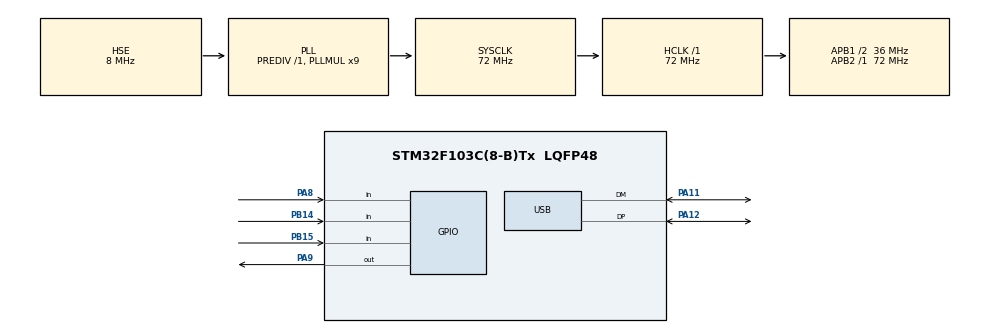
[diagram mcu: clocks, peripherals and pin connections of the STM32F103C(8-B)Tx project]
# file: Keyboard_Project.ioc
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Mcu.Family=STM32F1
Mcu.Name=STM32F103C(8-B)Tx
Mcu.Package=LQFP48
NVIC.PriorityGroup=NVIC_PRIORITYGROUP_4
NVIC.USB_LP_CAN1_RX0_IRQn=true\:0\:0\:false\:false\:true\:false\:true
PA11.Mode=Device
PA11.Signal=USB_DM
PA12.Mode=Device
PA12.Signal=USB_DP
PA13.Mode=Serial_Wire
PA13.Signal=SYS_JTMS-SWDIO
PA14.Mode=Serial_Wire
PA14.Signal=SYS_JTCK-SWCLK
PA8.Signal=GPIO_Input
PA9.Signal=GPIO_Output
PB14.Signal=GPIO_Input
PB15.Signal=GPIO_Input
PD0-OSC_IN.Mode=HSE-External-Oscillator
PD0-OSC_IN.Signal=RCC_OSC_IN
PD1-OSC_OUT.Mode=HSE-External-Oscillator
PD1-OSC_OUT.Signal=RCC_OSC_OUT
ProjectManager.HeapSize=0x200
ProjectManager.StackSize=0x400
ProjectManager.TargetToolchain=STM32CubeIDE
RCC.AHBFreq_Value=72000000
RCC.APB1CLKDivider=RCC_HCLK_DIV2
RCC.APB1Freq_Value=36000000
RCC.APB1TimFreq_Value=72000000
RCC.APB2Freq_Value=72000000
RCC.APB2TimFreq_Value=72000000
RCC.HCLKFreq_Value=72000000
RCC.PLLMUL=RCC_PLL_MUL9
RCC.SYSCLKFreq_VALUE=72000000
RCC.SYSCLKSource=RCC_SYSCLKSOURCE_PLLCLK
RCC.USBFreq_Value=48000000
RCC.USBPrescaler=RCC_USBCLKSOURCE_PLL_DIV1_5
USB_DEVICE.CLASS_NAME_FS=HID
USB_DEVICE.PRODUCT_STRING_HID_FS=Keyboard Project STM32
USB_DEVICE.VirtualMode=Hid
USB_DEVICE.VirtualModeFS=Hid_FS
VP_USB_DEVICE_VS_USB_DEVICE_HID_FS.Mode=HID_FS
board=custom

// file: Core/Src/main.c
/* USER CODE BEGIN Header */
/**
  ******************************************************************************
  * @file           : main.c
  * @brief          : Main program body
  ******************************************************************************
  * @attention
  *
  * <h2><center>&copy; Copyright (c) 2022 STMicroelectronics.
  * All rights reserved.</center></h2>
  *
  * This software component is licensed by ST under BSD 3-Clause license,
  * the "License"; You may not use this file except in compliance with the
  * License. You may obtain a copy of the License at:
  *                        opensource.org/licenses/BSD-3-Clause
  *
  ******************************************************************************
  */
/* USER CODE END Header */
#include "main.h"
#include "usb_device.h"

/* USER CODE BEGIN Includes */
#include "usbd_hid.h"
/* USER CODE END Includes */

void SystemClock_Config(void);
static void MX_GPIO_Init(void);

/* USER CODE BEGIN 0 */
extern USBD_HandleTypeDef hUsbDeviceFS; //variavel de outro arquivo por isso tem o extern
typedef struct
{
	uint8_t MODIFIER;
	uint8_t RESERVED;
	uint8_t KEYCODE1;
	uint8_t KEYCODE2;
	uint8_t KEYCODE3;
	uint8_t KEYCODE4;
	uint8_t KEYCODE5;
	uint8_t KEYCODE6;
} keyboardHID;

keyboardHID keyboardhid = {0,0,0,0,0,0,0,0};

/* USER CODE END 0 */

int main(void)
{

  /* MCU Configuration--------------------------------------------------------*/

  /* Reset of all peripherals, Initializes the Flash interface and the Systick. */
  HAL_Init();

  /* Configure the system clock */
  SystemClock_Config();

  /* Initialize all configured peripherals */
  MX_GPIO_Init();
  MX_USB_DEVICE_Init();

  /* Infinite loop */
  while (1)
  {

    /* USER CODE BEGIN 3 */

	  if(HAL_GPIO_ReadPin(GPIOB, GPIO_PIN_15) == 0 && HAL_GPIO_ReadPin(GPIOB, GPIO_PIN_14) == 1 && HAL_GPIO_ReadPin(GPIOB, GPIO_PIN_12) == 1 && HAL_GPIO_ReadPin(GPIOB, GPIO_PIN_13) == 1){
		  HAL_GPIO_WritePin(GPIOA,GPIO_PIN_8, 1);
		  	  keyboardhid.KEYCODE1 = 79; // right key
		 	  USBD_HID_SendReport(&hUsbDeviceFS, &keyboardhid, sizeof(keyboardhid)); // envia o report criado
		 	  HAL_Delay(50);
		 	  keyboardhid.KEYCODE1 = 0x00;// nenhuma tecla pressionada, caso soltar a tecla
		 	  USBD_HID_SendReport(&hUsbDeviceFS, &keyboardhid, sizeof(keyboardhid));
		 	  HAL_Delay(10);
		 	 HAL_GPIO_WritePin(GPIOA,GPIO_PIN_8, 0);

	  }

	 if(HAL_GPIO_ReadPin(GPIOB, GPIO_PIN_14) == 0 && HAL_GPIO_ReadPin(GPIOB, GPIO_PIN_15) == 1 && HAL_GPIO_ReadPin(GPIOB, GPIO_PIN_12) == 1 && HAL_GPIO_ReadPin(GPIOB, GPIO_PIN_13) == 1){
	  	  keyboardhid.KEYCODE1 = 80; // left key
	 	  USBD_HID_SendReport(&hUsbDeviceFS, &keyboardhid, sizeof(keyboardhid)); // envia o report criado

	 	  HAL_GPIO_WritePin(GPIOA,GPIO_PIN_9, 1);

	 	  HAL_Delay(50);
	 	  keyboardhid.KEYCODE1 = 0x00;// nenhuma tecla pressionada, caso soltar a tecla
	 	  USBD_HID_SendReport(&hUsbDeviceFS, &keyboardhid, sizeof(keyboardhid));
	 	  HAL_Delay(10);
	 	  HAL_GPIO_WritePin(GPIOA,GPIO_PIN_9, 0);
  }

	 if(HAL_GPIO_ReadPin(GPIOB, GPIO_PIN_12) == 0 && HAL_GPIO_ReadPin(GPIOB, GPIO_PIN_13) == 1  && HAL_GPIO_ReadPin(GPIOB, GPIO_PIN_14) == 1 && HAL_GPIO_ReadPin(GPIOB, GPIO_PIN_15) == 1){
	 		  HAL_GPIO_WritePin(GPIOA,GPIO_PIN_8, 1);
	 		  	  keyboardhid.KEYCODE1 = 81; // up key
	 		 	  USBD_HID_SendReport(&hUsbDeviceFS, &keyboardhid, sizeof(keyboardhid)); // envia o report criado
	 		 	  HAL_Delay(50);
	 		 	  keyboardhid.KEYCODE1 = 0x00;// nenhuma tecla pressionada, caso soltar a tecla
	 		 	  USBD_HID_SendReport(&hUsbDeviceFS, &keyboardhid, sizeof(keyboardhid));
	 		 	  HAL_Delay(10);
	 		 	 HAL_GPIO_WritePin(GPIOA,GPIO_PIN_8, 0);

	 	  }

	 	 if(HAL_GPIO_ReadPin(GPIOB, GPIO_PIN_13) == 0 && HAL_GPIO_ReadPin(GPIOB, GPIO_PIN_12) == 1 && HAL_GPIO_ReadPin(GPIOB, GPIO_PIN_14) == 1 && HAL_GPIO_ReadPin(GPIOB, GPIO_PIN_15) == 1){
	 	  	  keyboardhid.KEYCODE1 = 82; // down key
	 	 	  USBD_HID_SendReport(&hUsbDeviceFS, &keyboardhid, sizeof(keyboardhid)); // envia o report criado

	 	 	  HAL_GPIO_WritePin(GPIOA,GPIO_PIN_9, 1);

	 	 	  HAL_Delay(50);
	 	 	  keyboardhid.KEYCODE1 = 0x00;// nenhuma tecla pressionada, caso soltar a tecla
	 	 	  USBD_HID_SendReport(&hUsbDeviceFS, &keyboardhid, sizeof(keyboardhid));
	 	 	  HAL_Delay(10);
	 	 	  HAL_GPIO_WritePin(GPIOA,GPIO_PIN_9, 0);
	   }

  }
  /* USER CODE END 3 */
}

void SystemClock_Config(void)
{
  RCC_OscInitTypeDef RCC_OscInitStruct = {0};
  RCC_ClkInitTypeDef RCC_ClkInitStruct = {0};
  RCC_PeriphCLKInitTypeDef PeriphClkInit = {0};

  /** Initializes the RCC Oscillators according to the specified parameters
  * in the RCC_OscInitTypeDef structure.
  */
  RCC_OscInitStruct.OscillatorType = RCC_OSCILLATORTYPE_HSE;
  RCC_OscInitStruct.HSEState = RCC_HSE_ON;
  RCC_OscInitStruct.HSEPredivValue = RCC_HSE_PREDIV_DIV1;
  RCC_OscInitStruct.HSIState = RCC_HSI_ON;
  RCC_OscInitStruct.PLL.PLLState = RCC_PLL_ON;
  RCC_OscInitStruct.PLL.PLLSource = RCC_PLLSOURCE_HSE;
  RCC_OscInitStruct.PLL.PLLMUL = RCC_PLL_MUL9;
  if (HAL_RCC_OscConfig(&RCC_OscInitStruct) != HAL_OK)
  {
    Error_Handler();
  }
  /** Initializes the CPU, AHB and APB buses clocks
  */
  RCC_ClkInitStruct.ClockType = RCC_CLOCKTYPE_HCLK|RCC_CLOCKTYPE_SYSCLK
                              |RCC_CLOCKTYPE_PCLK1|RCC_CLOCKTYPE_PCLK2;
  RCC_ClkInitStruct.SYSCLKSource = RCC_SYSCLKSOURCE_PLLCLK;
  RCC_ClkInitStruct.AHBCLKDivider = RCC_SYSCLK_DIV1;
  RCC_ClkInitStruct.APB1CLKDivider = RCC_HCLK_DIV2;
  RCC_ClkInitStruct.APB2CLKDivider = RCC_HCLK_DIV1;

  if (HAL_RCC_ClockConfig(&RCC_ClkInitStruct, FLASH_LATENCY_2) != HAL_OK)
  {
    Error_Handler();
  }
  PeriphClkInit.PeriphClockSelection = RCC_PERIPHCLK_USB;
  PeriphClkInit.UsbClockSelection = RCC_USBCLKSOURCE_PLL_DIV1_5;
  if (HAL_RCCEx_PeriphCLKConfig(&PeriphClkInit) != HAL_OK)
  {
    Error_Handler();
  }
}

static void MX_GPIO_Init(void)
{
  GPIO_InitTypeDef GPIO_InitStruct = {0};

  /* GPIO Ports Clock Enable */
  __HAL_RCC_GPIOD_CLK_ENABLE();
  __HAL_RCC_GPIOB_CLK_ENABLE();
  __HAL_RCC_GPIOA_CLK_ENABLE();

  /*Configure GPIO pin Output Level */
  HAL_GPIO_WritePin(GPIOA, GPIO_PIN_8|GPIO_PIN_9, GPIO_PIN_RESET);

  /*Configure GPIO pins : PB12 PB13 PB14 PB15 */
  GPIO_InitStruct.Pin = GPIO_PIN_12|GPIO_PIN_13|GPIO_PIN_14|GPIO_PIN_15;
  GPIO_InitStruct.Mode = GPIO_MODE_INPUT;
  GPIO_InitStruct.Pull = GPIO_PULLUP;
  HAL_GPIO_Init(GPIOB, &GPIO_InitStruct);

  /*Configure GPIO pins : PA8 PA9 */
  GPIO_InitStruct.Pin = GPIO_PIN_8|GPIO_PIN_9;
  GPIO_InitStruct.Mode = GPIO_MODE_OUTPUT_PP;
  GPIO_InitStruct.Pull = GPIO_NOPULL;
  GPIO_InitStruct.Speed = GPIO_SPEED_FREQ_LOW;
  HAL_GPIO_Init(GPIOA, &GPIO_InitStruct);

}

void Error_Handler(void)
{
  __disable_irq();
  while (1)
  {
  }
}

/************************ (C) COPYRIGHT STMicroelectronics *****END OF FILE****/
